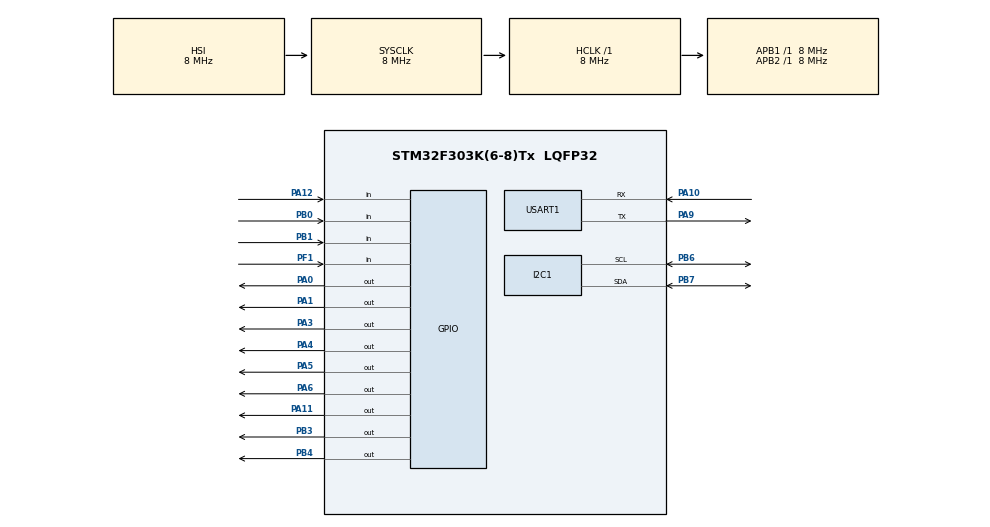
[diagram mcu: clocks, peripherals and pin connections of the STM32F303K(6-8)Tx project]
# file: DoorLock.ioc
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I2C1.Timing=0x00201D2B
Mcu.Family=STM32F3
Mcu.Name=STM32F303K(6-8)Tx
Mcu.Package=LQFP32
NVIC.PriorityGroup=NVIC_PRIORITYGROUP_4
PA0.Signal=GPIO_Output
PA1.Signal=GPIO_Output
PA10.Mode=Asynchronous
PA10.Signal=USART1_RX
PA11.Signal=GPIO_Output
PA12.Signal=GPIO_Input
PA13.GPIO_Label=SWDIO
PA13.Mode=Serial_Wire
PA13.Signal=SYS_JTMS-SWDIO
PA14.GPIO_Label=SWCLK
PA14.Mode=Serial_Wire
PA14.Signal=SYS_JTCK-SWCLK
PA15.Signal=USART2_RX
PA2.Signal=USART2_TX
PA3.Signal=GPIO_Output
PA4.Signal=GPIO_Output
PA5.Signal=GPIO_Output
PA6.Signal=GPIO_Output
PA9.Mode=Asynchronous
PA9.Signal=USART1_TX
PB0.Signal=GPIO_Input
PB1.Signal=GPIO_Input
PB3.Signal=GPIO_Output
PB4.Signal=GPIO_Output
PB6.Mode=I2C
PB6.Signal=I2C1_SCL
PB7.Mode=I2C
PB7.Signal=I2C1_SDA
PF0\ /\ OSC_IN.GPIO_Label=MCO
PF0\ /\ OSC_IN.Mode=HSE-External-Clock-Source
PF0\ /\ OSC_IN.Signal=RCC_OSC_IN
PF1\ /\ OSC_OUT.Signal=GPIO_Input
ProjectManager.HeapSize=0x200
ProjectManager.StackSize=0x400
ProjectManager.TargetToolchain=STM32CubeIDE
RCC.AHBFreq_Value=8000000
RCC.APB1Freq_Value=8000000
RCC.APB2Freq_Value=8000000
RCC.CortexFreq_Value=8000000
RCC.HSE_VALUE=8000000
RCC.HSI_VALUE=8000000
RCC.SYSCLKFreq_VALUE=8000000
TIM1.Prescaler=71
USART1.VirtualMode-Asynchronous=VM_ASYNC
VP_TIM1_VS_ClockSourceINT.Mode=Internal
VP_TIM3_VS_ClockSourceINT.Mode=Internal
board=NUCLEO-F303K8

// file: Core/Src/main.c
/* USER CODE BEGIN Header */
/**
  ******************************************************************************
  * @file           : main.c
  * @brief          : Main program body
  ******************************************************************************
  * @attention
  *
  * Copyright (c) 2024 STMicroelectronics.
  * All rights reserved.
  *
  * This software is licensed under terms that can be found in the LICENSE file
  * in the root directory of this software component.
  * If no LICENSE file comes with this software, it is provided AS-IS.
  *
  ******************************************************************************
  */
/* USER CODE END Header */
#include "main.h"
#include <stdio.h>
/* USER CODE BEGIN Includes */
#include "button_control.h"
#include "led_control.h"
#include "motor_control.h"
#include "eeprom_control.h"
/* USER CODE END Includes */

I2C_HandleTypeDef hi2c1;

TIM_HandleTypeDef htim1;
TIM_HandleTypeDef htim3;

UART_HandleTypeDef huart1;

void SystemClock_Config(void);
static void MX_GPIO_Init(void);
static void MX_I2C1_Init(void);
static void MX_USART1_UART_Init(void);
static void MX_TIM1_Init(void);
static void MX_TIM3_Init(void);
/* USER CODE BEGIN PFP */
void print(const char *str, uint16_t size)
{
	HAL_UART_Transmit(&huart1, (uint8_t *)str, size, HAL_MAX_DELAY);
}
/* USER CODE END PFP */

int main(void)
{

  /* USER CODE BEGIN 1 */
  uint8_t state = ePASSIVE;
  bool lockStatus = eLOCKED;
  uint8_t rtv;

  // Read EEPROM for lock state;

  /* USER CODE END 1 */

  /* MCU Configuration--------------------------------------------------------*/

  /* Reset of all peripherals, Initializes the Flash interface and the Systick. */
  HAL_Init();

  /* USER CODE BEGIN Init */

  //readEEPROM();

  /* USER CODE END Init */

  /* Configure the system clock */
  SystemClock_Config();

  /* Initialize all configured peripherals */
  MX_GPIO_Init();
  MX_I2C1_Init();
  MX_USART1_UART_Init();
  MX_TIM1_Init();
  MX_TIM3_Init();
  /* USER CODE BEGIN 2 */
  //pendingLED();
  /* USER CODE END 2 */

  /* Infinite loop */
  /* USER CODE BEGIN WHILE */
  while (1)
  {
	switch(state)
	{
	case ePASSIVE:
		rtv = actionEnterPasscode();

		if(rtv == RETURN_SUCCESS){
			if(lockStatus == eLOCKED)
			{
				char msg[] = "\nCorrect Passcode Entered";
				print(msg, sizeof(msg));
				successLED();
				state = eLOCKING;
			}
			else
			{
				char msg[] = "\nAlready Unlocked";
				print(msg, sizeof(msg));
				disableLED();
			}
		}
		else if(rtv == RETURN_FAILURE){
			char msg[] = "\nIncorrect Passcode Entered";
			print(msg, sizeof(msg));
			errorLED();
		}
		else if(rtv == BUTTON_LOCK){
			if(lockStatus == eUNLOCKED)
			{
				char msg[] = "\nUnlocking/Locking Door";
				print(msg, sizeof(msg));
				successLED();
				state = eLOCKING;
			}
			else
			{
				char msg[] = "\nAlready Locked";
				print(msg, sizeof(msg));
				disableLED();
			}
		}
		else if(rtv == BUTTON_EDIT){
			char msg[] = "\nEditing Passcode";
			print(msg, sizeof(msg));
			disableLED();
			state = eSETTING_PASSCODE;
		}
		else if(rtv == RETURN_PENDING) 	{ pendingLED(); }

		break;

	case eLOCKING:
		lockStatus = !lockStatus;
		powerMotor(lockStatus, 1000U);
		state = ePASSIVE;

	    break;

	case eSETTING_PASSCODE:
		rtv = actionSetPasscode();

		if(rtv == RETURN_SUCCESS){
			char msg[] = "\nPasscode Successfully Set";
			print(msg, sizeof(msg));
			successLED();
			state = ePASSIVE;
		}
		else if(rtv == RETURN_FAILURE){
			char msg[] = "\nPasscode Unsuccessfully Set";
			print(msg, sizeof(msg));
			errorLED();
			state = ePASSIVE;
		}
		else if(rtv == BUTTON_LOCK){
			char msg[] = "\nAborting Passcode Change";
			print(msg, sizeof(msg));
			disableLED();
			state = ePASSIVE;
		}
		else if(rtv == RETURN_PENDING) 	{ pendingLED(); }

		break;

	default:
		break;
	}

	blinkLED();
	HAL_Delay(50);
    /* USER CODE END WHILE */

  }
}

void SystemClock_Config(void)
{
  RCC_OscInitTypeDef RCC_OscInitStruct = {0};
  RCC_ClkInitTypeDef RCC_ClkInitStruct = {0};
  RCC_PeriphCLKInitTypeDef PeriphClkInit = {0};

  /** Initializes the RCC Oscillators according to the specified parameters
  * in the RCC_OscInitTypeDef structure.
  */
  RCC_OscInitStruct.OscillatorType = RCC_OSCILLATORTYPE_HSI;
  RCC_OscInitStruct.HSIState = RCC_HSI_ON;
  RCC_OscInitStruct.HSICalibrationValue = RCC_HSICALIBRATION_DEFAULT;
  RCC_OscInitStruct.PLL.PLLState = RCC_PLL_NONE;
  if (HAL_RCC_OscConfig(&RCC_OscInitStruct) != HAL_OK)
  {
    Error_Handler();
  }

  /** Initializes the CPU, AHB and APB buses clocks
  */
  RCC_ClkInitStruct.ClockType = RCC_CLOCKTYPE_HCLK|RCC_CLOCKTYPE_SYSCLK
                              |RCC_CLOCKTYPE_PCLK1|RCC_CLOCKTYPE_PCLK2;
  RCC_ClkInitStruct.SYSCLKSource = RCC_SYSCLKSOURCE_HSI;
  RCC_ClkInitStruct.AHBCLKDivider = RCC_SYSCLK_DIV1;
  RCC_ClkInitStruct.APB1CLKDivider = RCC_HCLK_DIV1;
  RCC_ClkInitStruct.APB2CLKDivider = RCC_HCLK_DIV1;

  if (HAL_RCC_ClockConfig(&RCC_ClkInitStruct, FLASH_LATENCY_0) != HAL_OK)
  {
    Error_Handler();
  }
  PeriphClkInit.PeriphClockSelection = RCC_PERIPHCLK_USART1|RCC_PERIPHCLK_I2C1
                              |RCC_PERIPHCLK_TIM1;
  PeriphClkInit.Usart1ClockSelection = RCC_USART1CLKSOURCE_PCLK1;
  PeriphClkInit.I2c1ClockSelection = RCC_I2C1CLKSOURCE_HSI;
  PeriphClkInit.Tim1ClockSelection = RCC_TIM1CLK_HCLK;
  if (HAL_RCCEx_PeriphCLKConfig(&PeriphClkInit) != HAL_OK)
  {
    Error_Handler();
  }
}

static void MX_I2C1_Init(void)
{

  hi2c1.Instance = I2C1;
  hi2c1.Init.Timing = 0x00201D2B;
  hi2c1.Init.OwnAddress1 = 0;
  hi2c1.Init.AddressingMode = I2C_ADDRESSINGMODE_7BIT;
  hi2c1.Init.DualAddressMode = I2C_DUALADDRESS_DISABLE;
  hi2c1.Init.OwnAddress2 = 0;
  hi2c1.Init.OwnAddress2Masks = I2C_OA2_NOMASK;
  hi2c1.Init.GeneralCallMode = I2C_GENERALCALL_DISABLE;
  hi2c1.Init.NoStretchMode = I2C_NOSTRETCH_DISABLE;
  if (HAL_I2C_Init(&hi2c1) != HAL_OK)
  {
    Error_Handler();
  }

  /** Configure Analogue filter
  */
  if (HAL_I2CEx_ConfigAnalogFilter(&hi2c1, I2C_ANALOGFILTER_ENABLE) != HAL_OK)
  {
    Error_Handler();
  }

  /** Configure Digital filter
  */
  if (HAL_I2CEx_ConfigDigitalFilter(&hi2c1, 0) != HAL_OK)
  {
    Error_Handler();
  }

}

static void MX_TIM1_Init(void)
{

  TIM_ClockConfigTypeDef sClockSourceConfig = {0};
  TIM_MasterConfigTypeDef sMasterConfig = {0};

  htim1.Instance = TIM1;
  htim1.Init.Prescaler = 8000;
  htim1.Init.CounterMode = TIM_COUNTERMODE_UP;
  htim1.Init.Period = 65535;
  htim1.Init.ClockDivision = TIM_CLOCKDIVISION_DIV1;
  htim1.Init.RepetitionCounter = 0;
  htim1.Init.AutoReloadPreload = TIM_AUTORELOAD_PRELOAD_DISABLE;
  if (HAL_TIM_Base_Init(&htim1) != HAL_OK)
  {
    Error_Handler();
  }
  sClockSourceConfig.ClockSource = TIM_CLOCKSOURCE_INTERNAL;
  if (HAL_TIM_ConfigClockSource(&htim1, &sClockSourceConfig) != HAL_OK)
  {
    Error_Handler();
  }
  sMasterConfig.MasterOutputTrigger = TIM_TRGO_RESET;
  sMasterConfig.MasterOutputTrigger2 = TIM_TRGO2_RESET;
  sMasterConfig.MasterSlaveMode = TIM_MASTERSLAVEMODE_DISABLE;
  if (HAL_TIMEx_MasterConfigSynchronization(&htim1, &sMasterConfig) != HAL_OK)
  {
    Error_Handler();
  }

}

static void MX_TIM3_Init(void)
{

  TIM_ClockConfigTypeDef sClockSourceConfig = {0};
  TIM_MasterConfigTypeDef sMasterConfig = {0};

  htim3.Instance = TIM3;
  htim3.Init.Prescaler = 8000;
  htim3.Init.CounterMode = TIM_COUNTERMODE_UP;
  htim3.Init.Period = 65535;
  htim3.Init.ClockDivision = TIM_CLOCKDIVISION_DIV1;
  htim3.Init.AutoReloadPreload = TIM_AUTORELOAD_PRELOAD_DISABLE;
  if (HAL_TIM_Base_Init(&htim3) != HAL_OK)
  {
    Error_Handler();
  }
  sClockSourceConfig.ClockSource = TIM_CLOCKSOURCE_INTERNAL;
  if (HAL_TIM_ConfigClockSource(&htim3, &sClockSourceConfig) != HAL_OK)
  {
    Error_Handler();
  }
  sMasterConfig.MasterOutputTrigger = TIM_TRGO_RESET;
  sMasterConfig.MasterSlaveMode = TIM_MASTERSLAVEMODE_DISABLE;
  if (HAL_TIMEx_MasterConfigSynchronization(&htim3, &sMasterConfig) != HAL_OK)
  {
    Error_Handler();
  }
  /* USER CODE BEGIN TIM3_Init 2 */
  HAL_TIM_Base_Start(&htim3);
  /* USER CODE END TIM3_Init 2 */

}

static void MX_USART1_UART_Init(void)
{

  huart1.Instance = USART1;
  huart1.Init.BaudRate = 115200;
  huart1.Init.WordLength = UART_WORDLENGTH_8B;
  huart1.Init.StopBits = UART_STOPBITS_1;
  huart1.Init.Parity = UART_PARITY_NONE;
  huart1.Init.Mode = UART_MODE_TX_RX;
  huart1.Init.HwFlowCtl = UART_HWCONTROL_NONE;
  huart1.Init.OverSampling = UART_OVERSAMPLING_16;
  huart1.Init.OneBitSampling = UART_ONE_BIT_SAMPLE_DISABLE;
  huart1.AdvancedInit.AdvFeatureInit = UART_ADVFEATURE_NO_INIT;
  if (HAL_UART_Init(&huart1) != HAL_OK)
  {
    Error_Handler();
  }

}

static void MX_GPIO_Init(void)
{
  GPIO_InitTypeDef GPIO_InitStruct = {0};

  /* GPIO Ports Clock Enable */
  __HAL_RCC_GPIOF_CLK_ENABLE();
  __HAL_RCC_GPIOA_CLK_ENABLE();
  __HAL_RCC_GPIOB_CLK_ENABLE();

  /*Configure GPIO pin Output Level */
  HAL_GPIO_WritePin(GPIOA, LED_1_Pin|LED_2_Pin|LED_3_Pin|LED_4_Pin
                          |DIR_Pin|STEP_Pin|COL_2_Pin, GPIO_PIN_RESET);

  /*Configure GPIO pin Output Level */
  HAL_GPIO_WritePin(GPIOB, COL_1_Pin|COL_3_Pin, GPIO_PIN_RESET);

  /*Configure GPIO pin : ROW_1_Pin */
  GPIO_InitStruct.Pin = ROW_1_Pin;
  GPIO_InitStruct.Mode = GPIO_MODE_INPUT;
  GPIO_InitStruct.Pull = GPIO_NOPULL;
  HAL_GPIO_Init(ROW_1_GPIO_Port, &GPIO_InitStruct);

  /*Configure GPIO pins : LED_1_Pin LED_2_Pin LED_3_Pin LED_4_Pin
                           DIR_Pin STEP_Pin COL_2_Pin */
  GPIO_InitStruct.Pin = LED_1_Pin|LED_2_Pin|LED_3_Pin|LED_4_Pin
                          |DIR_Pin|STEP_Pin|COL_2_Pin;
  GPIO_InitStruct.Mode = GPIO_MODE_OUTPUT_PP;
  GPIO_InitStruct.Pull = GPIO_NOPULL;
  GPIO_InitStruct.Speed = GPIO_SPEED_FREQ_LOW;
  HAL_GPIO_Init(GPIOA, &GPIO_InitStruct);

  /*Configure GPIO pins : PA2 PA15 */
  GPIO_InitStruct.Pin = GPIO_PIN_2|GPIO_PIN_15;
  GPIO_InitStruct.Mode = GPIO_MODE_AF_PP;
  GPIO_InitStruct.Pull = GPIO_NOPULL;
  GPIO_InitStruct.Speed = GPIO_SPEED_FREQ_HIGH;
  GPIO_InitStruct.Alternate = GPIO_AF7_USART2;
  HAL_GPIO_Init(GPIOA, &GPIO_InitStruct);

  /*Configure GPIO pins : ROW_3_Pin ROW_2_Pin */
  GPIO_InitStruct.Pin = ROW_3_Pin|ROW_2_Pin;
  GPIO_InitStruct.Mode = GPIO_MODE_INPUT;
  GPIO_InitStruct.Pull = GPIO_NOPULL;
  HAL_GPIO_Init(GPIOB, &GPIO_InitStruct);

  /*Configure GPIO pin : ROW_4_Pin */
  GPIO_InitStruct.Pin = ROW_4_Pin;
  GPIO_InitStruct.Mode = GPIO_MODE_INPUT;
  GPIO_InitStruct.Pull = GPIO_NOPULL;
  HAL_GPIO_Init(ROW_4_GPIO_Port, &GPIO_InitStruct);

  /*Configure GPIO pins : COL_1_Pin COL_3_Pin */
  GPIO_InitStruct.Pin = COL_1_Pin|COL_3_Pin;
  GPIO_InitStruct.Mode = GPIO_MODE_OUTPUT_PP;
  GPIO_InitStruct.Pull = GPIO_NOPULL;
  GPIO_InitStruct.Speed = GPIO_SPEED_FREQ_LOW;
  HAL_GPIO_Init(GPIOB, &GPIO_InitStruct);

}

void Error_Handler(void)
{
  __disable_irq();
  while (1)
  {
  }
}
